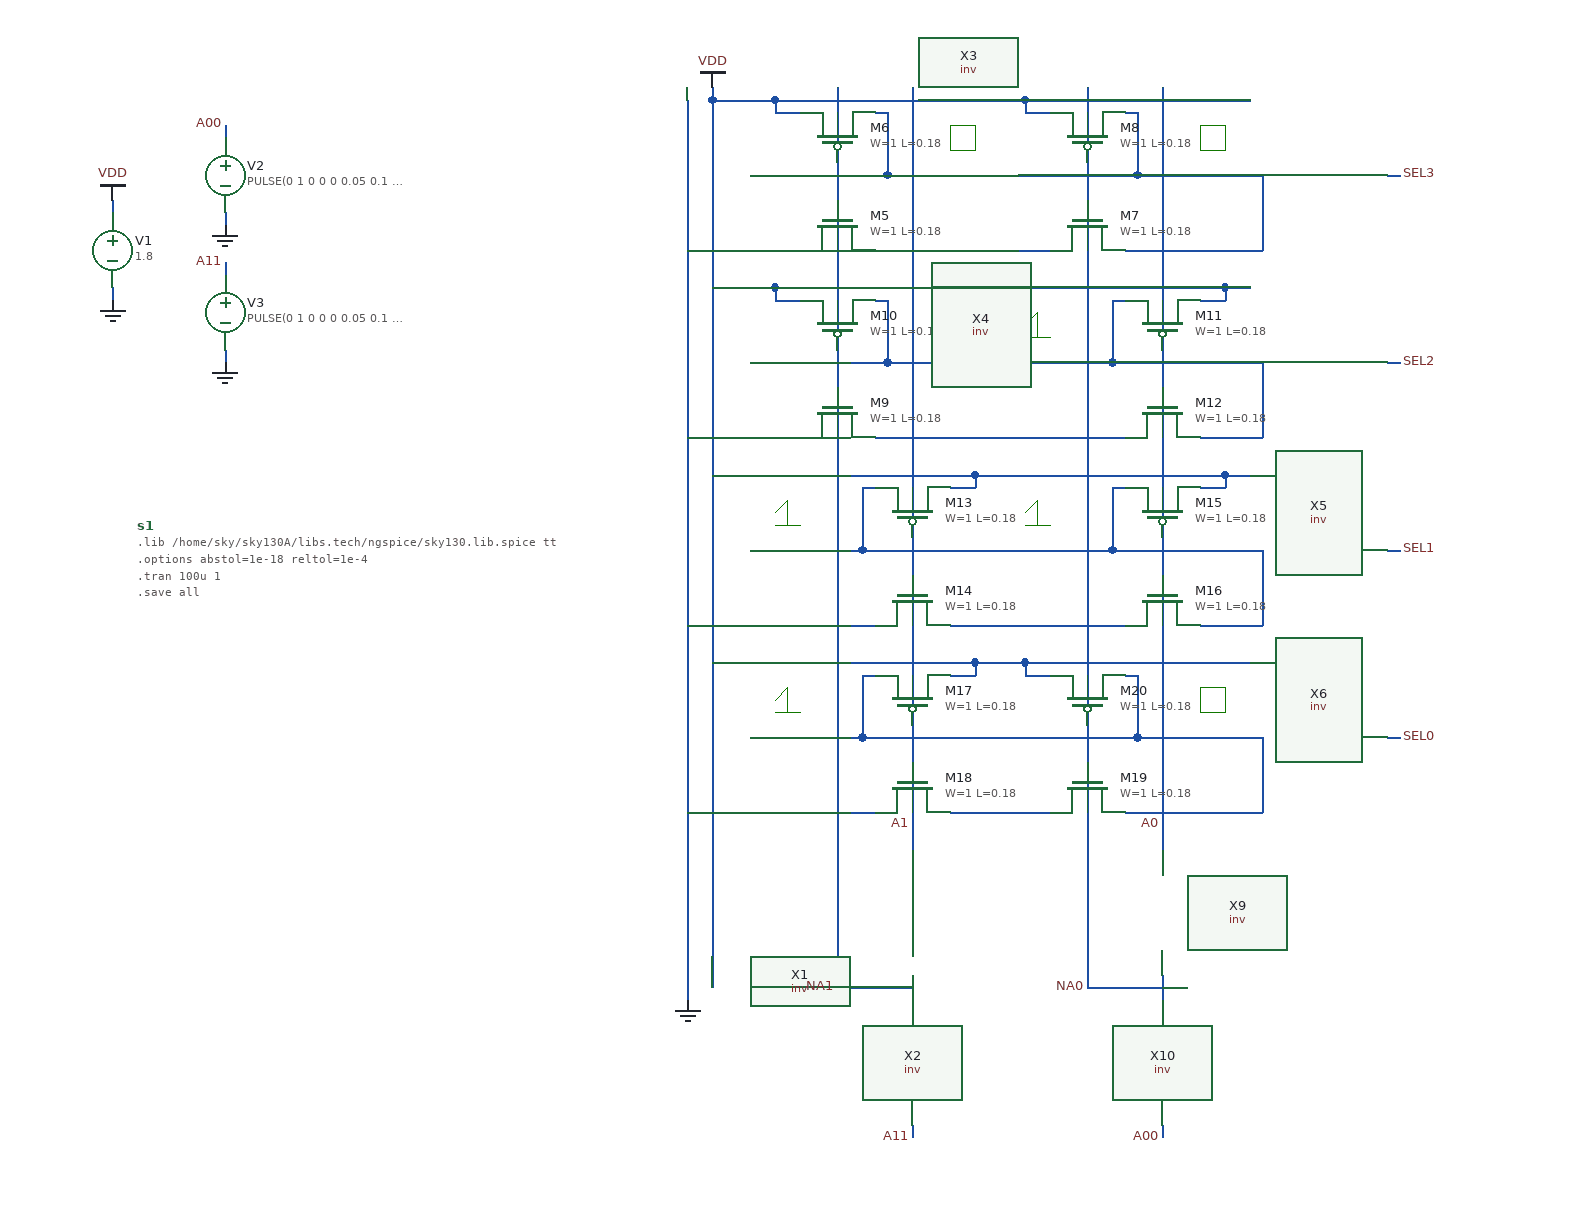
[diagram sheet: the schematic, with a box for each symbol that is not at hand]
v {xschem version=2.9.9 file_version=1.2 }
G {}
K {}
V {}
S {}
E {}
L 4 1500 -1330 1500 -1310 {}
L 4 1500 -1310 1520 -1310 {}
L 4 1520 -1330 1520 -1310 {}
L 4 1500 -1330 1520 -1330 {}
L 4 1700 -1330 1700 -1310 {}
L 4 1700 -1310 1720 -1310 {}
L 4 1720 -1330 1720 -1310 {}
L 4 1700 -1330 1720 -1330 {}
L 4 1500 -1180 1500 -1160 {}
L 4 1500 -1160 1520 -1160 {}
L 4 1520 -1180 1520 -1160 {}
L 4 1500 -1180 1520 -1180 {}
L 4 1560 -1170 1570 -1180 {}
L 4 1570 -1180 1570 -1160 {}
L 4 1560 -1160 1570 -1160 {}
L 4 1560 -1160 1580 -1160 {}
L 4 1360 -1020 1370 -1030 {}
L 4 1370 -1030 1370 -1010 {}
L 4 1360 -1010 1370 -1010 {}
L 4 1360 -1010 1380 -1010 {}
L 4 1560 -1020 1570 -1030 {}
L 4 1570 -1030 1570 -1010 {}
L 4 1560 -1010 1570 -1010 {}
L 4 1560 -1010 1580 -1010 {}
L 4 1360 -870 1370 -880 {}
L 4 1370 -880 1370 -860 {}
L 4 1360 -860 1370 -860 {}
L 4 1360 -860 1380 -860 {}
L 4 1700 -880 1700 -860 {}
L 4 1700 -860 1720 -860 {}
L 4 1720 -880 1720 -860 {}
L 4 1700 -880 1720 -880 {}
N 1360 -1340 1380 -1340 { lab=VDD}
N 1360 -1350 1360 -1340 { lab=VDD}
N 1340 -1350 1360 -1350 { lab=VDD}
N 1410 -1300 1410 -1270 { lab=NA1}
N 1410 -1270 1410 -1210 { lab=NA1}
N 1410 -1360 1410 -1300 { lab=NA1}
N 1440 -1340 1450 -1340 { lab=#net1}
N 1450 -1340 1450 -1290 { lab=#net1}
N 1340 -1290 1450 -1290 { lab=#net1}
N 1340 -1230 1380 -1230 { lab=GND}
N 1470 -1360 1470 -1210 { lab=A1}
N 1360 -1350 1540 -1350 { lab=VDD}
N 1450 -1290 1540 -1290 { lab=#net1}
N 1440 -1230 1540 -1230 { lab=#net2}
N 1560 -1340 1580 -1340 { lab=VDD}
N 1560 -1350 1560 -1340 { lab=VDD}
N 1540 -1350 1560 -1350 { lab=VDD}
N 1610 -1300 1610 -1270 { lab=NA0}
N 1610 -1270 1610 -1210 { lab=NA0}
N 1610 -1360 1610 -1300 { lab=NA0}
N 1640 -1340 1650 -1340 { lab=#net1}
N 1650 -1340 1650 -1290 { lab=#net1}
N 1540 -1290 1650 -1290 { lab=#net1}
N 1540 -1230 1580 -1230 { lab=#net2}
N 1670 -1360 1670 -1210 { lab=A0}
N 1560 -1350 1740 -1350 { lab=VDD}
N 1650 -1290 1740 -1290 { lab=#net1}
N 1640 -1230 1740 -1230 { lab=#net1}
N 1360 -1190 1380 -1190 { lab=VDD}
N 1360 -1200 1360 -1190 { lab=VDD}
N 1340 -1200 1360 -1200 { lab=VDD}
N 1410 -1150 1410 -1120 { lab=NA1}
N 1410 -1120 1410 -1060 { lab=NA1}
N 1410 -1210 1410 -1150 { lab=NA1}
N 1440 -1190 1450 -1190 { lab=#net3}
N 1450 -1190 1450 -1140 { lab=#net3}
N 1340 -1140 1450 -1140 { lab=#net3}
N 1340 -1080 1380 -1080 { lab=GND}
N 1470 -1210 1470 -1060 { lab=A1}
N 1360 -1200 1540 -1200 { lab=VDD}
N 1450 -1140 1540 -1140 { lab=#net3}
N 1440 -1080 1540 -1080 { lab=#net4}
N 1700 -1190 1720 -1190 { lab=VDD}
N 1720 -1200 1720 -1190 { lab=VDD}
N 1720 -1200 1740 -1200 { lab=VDD}
N 1540 -1200 1720 -1200 { lab=VDD}
N 1630 -1190 1640 -1190 { lab=#net3}
N 1630 -1190 1630 -1140 { lab=#net3}
N 1540 -1140 1630 -1140 { lab=#net3}
N 1630 -1140 1740 -1140 { lab=#net3}
N 1670 -1150 1670 -1120 { lab=A0}
N 1670 -1210 1670 -1150 { lab=A0}
N 1670 -1120 1670 -1060 { lab=A0}
N 1540 -1080 1640 -1080 { lab=#net4}
N 1700 -1080 1740 -1080 { lab=#net3}
N 1610 -1210 1610 -1060 { lab=NA0}
N 1500 -1040 1520 -1040 { lab=VDD}
N 1520 -1050 1520 -1040 { lab=VDD}
N 1520 -1050 1540 -1050 { lab=VDD}
N 1340 -1050 1520 -1050 { lab=VDD}
N 1430 -1040 1440 -1040 { lab=#net5}
N 1430 -1040 1430 -990 { lab=#net5}
N 1340 -990 1430 -990 { lab=#net5}
N 1430 -990 1540 -990 { lab=#net5}
N 1470 -1000 1470 -970 { lab=A1}
N 1470 -1060 1470 -1000 { lab=A1}
N 1470 -970 1470 -910 { lab=A1}
N 1340 -930 1440 -930 { lab=GND}
N 1500 -930 1540 -930 { lab=#net6}
N 1410 -1060 1410 -910 { lab=NA1}
N 1700 -1040 1720 -1040 { lab=VDD}
N 1720 -1050 1720 -1040 { lab=VDD}
N 1720 -1050 1740 -1050 { lab=VDD}
N 1540 -1050 1720 -1050 { lab=VDD}
N 1630 -1040 1640 -1040 { lab=#net5}
N 1630 -1040 1630 -990 { lab=#net5}
N 1540 -990 1630 -990 { lab=#net5}
N 1630 -990 1740 -990 { lab=#net5}
N 1670 -1000 1670 -970 { lab=A0}
N 1670 -1060 1670 -1000 { lab=A0}
N 1670 -970 1670 -910 { lab=A0}
N 1540 -930 1640 -930 { lab=#net6}
N 1700 -930 1740 -930 { lab=#net5}
N 1610 -1060 1610 -910 { lab=NA0}
N 1500 -890 1520 -890 { lab=VDD}
N 1520 -900 1520 -890 { lab=VDD}
N 1520 -900 1540 -900 { lab=VDD}
N 1340 -900 1520 -900 { lab=VDD}
N 1430 -890 1440 -890 { lab=#net7}
N 1430 -890 1430 -840 { lab=#net7}
N 1340 -840 1430 -840 { lab=#net7}
N 1430 -840 1540 -840 { lab=#net7}
N 1470 -850 1470 -820 { lab=A1}
N 1470 -910 1470 -850 { lab=A1}
N 1470 -820 1470 -760 { lab=A1}
N 1340 -780 1440 -780 { lab=GND}
N 1500 -780 1540 -780 { lab=#net8}
N 1410 -910 1410 -760 { lab=NA1}
N 1560 -890 1580 -890 { lab=VDD}
N 1560 -900 1560 -890 { lab=VDD}
N 1540 -900 1560 -900 { lab=VDD}
N 1610 -850 1610 -820 { lab=NA0}
N 1610 -820 1610 -760 { lab=NA0}
N 1610 -910 1610 -850 { lab=NA0}
N 1640 -890 1650 -890 { lab=#net7}
N 1650 -890 1650 -840 { lab=#net7}
N 1540 -840 1650 -840 { lab=#net7}
N 1540 -780 1580 -780 { lab=#net8}
N 1670 -910 1670 -760 { lab=A0}
N 1560 -900 1740 -900 { lab=VDD}
N 1650 -840 1740 -840 { lab=#net7}
N 1640 -780 1740 -780 { lab=#net7}
N 830 -1270 830 -1260 { lab=VDD}
N 830 -1200 830 -1190 { lab=GND}
N 920 -1260 920 -1250 { lab=GND}
N 920 -1150 920 -1140 { lab=GND}
N 920 -1220 920 -1210 { lab=A11}
N 920 -1330 920 -1320 { lab=A00}
N 1670 -650 1670 -630 { lab=NA0}
N 1670 -760 1670 -750 { lab=A0}
N 1640 -640 1670 -640 { lab=NA0}
N 1670 -530 1670 -520 { lab=A00}
N 1610 -760 1610 -640 { lab=NA0}
N 1610 -640 1640 -640 { lab=NA0}
N 1470 -650 1470 -630 { lab=NA1}
N 1470 -760 1470 -750 { lab=A1}
N 1440 -640 1470 -640 { lab=NA1}
N 1470 -530 1470 -520 { lab=A11}
N 1410 -760 1410 -640 { lab=NA1}
N 1410 -640 1440 -640 { lab=NA1}
N 1290 -1350 1290 -640 { lab=GND}
N 1310 -1350 1310 -640 { lab=VDD}
N 1310 -1360 1310 -1350 { lab=VDD}
N 1290 -640 1290 -630 { lab=GND}
N 1310 -1350 1340 -1350 { lab=VDD}
N 1290 -1230 1340 -1230 { lab=GND}
N 1310 -1200 1340 -1200 { lab=VDD}
N 1290 -1080 1340 -1080 { lab=GND}
N 1310 -1050 1340 -1050 { lab=VDD}
N 1290 -930 1340 -930 { lab=GND}
N 1310 -900 1340 -900 { lab=VDD}
N 1290 -780 1340 -780 { lab=GND}
N 1740 -1290 1750 -1290 { lab=#net1}
N 1750 -1290 1750 -1230 { lab=#net1}
N 1740 -1230 1750 -1230 { lab=#net1}
N 1740 -1140 1750 -1140 { lab=#net3}
N 1750 -1140 1750 -1080 { lab=#net3}
N 1740 -1080 1750 -1080 { lab=#net3}
N 1740 -990 1750 -990 { lab=#net5}
N 1750 -990 1750 -930 { lab=#net5}
N 1740 -930 1750 -930 { lab=#net5}
N 1740 -840 1750 -840 { lab=#net7}
N 1750 -840 1750 -780 { lab=#net7}
N 1740 -780 1750 -780 { lab=#net7}
N 1850 -840 1860 -840 { lab=SEL0}
N 1850 -990 1860 -990 { lab=SEL1}
N 1850 -1140 1860 -1140 { lab=SEL2}
N 1850 -1290 1860 -1290 { lab=SEL3}
C {sky130_fd_pr/nfet3_01v8.sym} 1410 -1250 1 0 {name=M5
L=0.18
W=1
body=GND
nf=1
mult=1
ad="'int((nf+1)/2) * W/nf * 0.29'" 
pd="'2*int((nf+1)/2) * (W/nf + 0.29)'"
as="'int((nf+2)/2) * W/nf * 0.29'" 
ps="'2*int((nf+2)/2) * (W/nf + 0.29)'"
nrd="'0.29 / W'" nrs="'0.29 / W'"
sa=0 sb=0 sd=0
model=nfet_01v8
spiceprefix=X
}
C {sky130_fd_pr/pfet3_01v8.sym} 1410 -1320 3 0 {name=M6
L=0.18
W=1
body=VDD
nf=1
mult=1
ad="'int((nf+1)/2) * W/nf * 0.29'" 
pd="'2*int((nf+1)/2) * (W/nf + 0.29)'"
as="'int((nf+2)/2) * W/nf * 0.29'" 
ps="'2*int((nf+2)/2) * (W/nf + 0.29)'"
nrd="'0.29 / W'" nrs="'0.29 / W'"
sa=0 sb=0 sd=0
model=pfet_01v8
spiceprefix=X
}
C {sky130_fd_pr/nfet3_01v8.sym} 1610 -1250 1 0 {name=M7
L=0.18
W=1
body=GND
nf=1
mult=1
ad="'int((nf+1)/2) * W/nf * 0.29'" 
pd="'2*int((nf+1)/2) * (W/nf + 0.29)'"
as="'int((nf+2)/2) * W/nf * 0.29'" 
ps="'2*int((nf+2)/2) * (W/nf + 0.29)'"
nrd="'0.29 / W'" nrs="'0.29 / W'"
sa=0 sb=0 sd=0
model=nfet_01v8
spiceprefix=X
}
C {sky130_fd_pr/pfet3_01v8.sym} 1610 -1320 3 0 {name=M8
L=0.18
W=1
body=VDD
nf=1
mult=1
ad="'int((nf+1)/2) * W/nf * 0.29'" 
pd="'2*int((nf+1)/2) * (W/nf + 0.29)'"
as="'int((nf+2)/2) * W/nf * 0.29'" 
ps="'2*int((nf+2)/2) * (W/nf + 0.29)'"
nrd="'0.29 / W'" nrs="'0.29 / W'"
sa=0 sb=0 sd=0
model=pfet_01v8
spiceprefix=X
}
C {sky130_fd_pr/nfet3_01v8.sym} 1410 -1100 1 0 {name=M9
L=0.18
W=1
body=GND
nf=1
mult=1
ad="'int((nf+1)/2) * W/nf * 0.29'" 
pd="'2*int((nf+1)/2) * (W/nf + 0.29)'"
as="'int((nf+2)/2) * W/nf * 0.29'" 
ps="'2*int((nf+2)/2) * (W/nf + 0.29)'"
nrd="'0.29 / W'" nrs="'0.29 / W'"
sa=0 sb=0 sd=0
model=nfet_01v8
spiceprefix=X
}
C {sky130_fd_pr/pfet3_01v8.sym} 1410 -1170 3 0 {name=M10
L=0.18
W=1
body=VDD
nf=1
mult=1
ad="'int((nf+1)/2) * W/nf * 0.29'" 
pd="'2*int((nf+1)/2) * (W/nf + 0.29)'"
as="'int((nf+2)/2) * W/nf * 0.29'" 
ps="'2*int((nf+2)/2) * (W/nf + 0.29)'"
nrd="'0.29 / W'" nrs="'0.29 / W'"
sa=0 sb=0 sd=0
model=pfet_01v8
spiceprefix=X
}
C {sky130_fd_pr/pfet3_01v8.sym} 1670 -1170 1 1 {name=M11
L=0.18
W=1
body=VDD
nf=1
mult=1
ad="'int((nf+1)/2) * W/nf * 0.29'" 
pd="'2*int((nf+1)/2) * (W/nf + 0.29)'"
as="'int((nf+2)/2) * W/nf * 0.29'" 
ps="'2*int((nf+2)/2) * (W/nf + 0.29)'"
nrd="'0.29 / W'" nrs="'0.29 / W'"
sa=0 sb=0 sd=0
model=pfet_01v8
spiceprefix=X
}
C {sky130_fd_pr/nfet3_01v8.sym} 1670 -1100 3 1 {name=M12
L=0.18
W=1
body=GND
nf=1
mult=1
ad="'int((nf+1)/2) * W/nf * 0.29'" 
pd="'2*int((nf+1)/2) * (W/nf + 0.29)'"
as="'int((nf+2)/2) * W/nf * 0.29'" 
ps="'2*int((nf+2)/2) * (W/nf + 0.29)'"
nrd="'0.29 / W'" nrs="'0.29 / W'"
sa=0 sb=0 sd=0
model=nfet_01v8
spiceprefix=X
}
C {sky130_fd_pr/pfet3_01v8.sym} 1470 -1020 1 1 {name=M13
L=0.18
W=1
body=VDD
nf=1
mult=1
ad="'int((nf+1)/2) * W/nf * 0.29'" 
pd="'2*int((nf+1)/2) * (W/nf + 0.29)'"
as="'int((nf+2)/2) * W/nf * 0.29'" 
ps="'2*int((nf+2)/2) * (W/nf + 0.29)'"
nrd="'0.29 / W'" nrs="'0.29 / W'"
sa=0 sb=0 sd=0
model=pfet_01v8
spiceprefix=X
}
C {sky130_fd_pr/nfet3_01v8.sym} 1470 -950 3 1 {name=M14
L=0.18
W=1
body=GND
nf=1
mult=1
ad="'int((nf+1)/2) * W/nf * 0.29'" 
pd="'2*int((nf+1)/2) * (W/nf + 0.29)'"
as="'int((nf+2)/2) * W/nf * 0.29'" 
ps="'2*int((nf+2)/2) * (W/nf + 0.29)'"
nrd="'0.29 / W'" nrs="'0.29 / W'"
sa=0 sb=0 sd=0
model=nfet_01v8
spiceprefix=X
}
C {sky130_fd_pr/pfet3_01v8.sym} 1670 -1020 1 1 {name=M15
L=0.18
W=1
body=VDD
nf=1
mult=1
ad="'int((nf+1)/2) * W/nf * 0.29'" 
pd="'2*int((nf+1)/2) * (W/nf + 0.29)'"
as="'int((nf+2)/2) * W/nf * 0.29'" 
ps="'2*int((nf+2)/2) * (W/nf + 0.29)'"
nrd="'0.29 / W'" nrs="'0.29 / W'"
sa=0 sb=0 sd=0
model=pfet_01v8
spiceprefix=X
}
C {sky130_fd_pr/nfet3_01v8.sym} 1670 -950 3 1 {name=M16
L=0.18
W=1
body=GND
nf=1
mult=1
ad="'int((nf+1)/2) * W/nf * 0.29'" 
pd="'2*int((nf+1)/2) * (W/nf + 0.29)'"
as="'int((nf+2)/2) * W/nf * 0.29'" 
ps="'2*int((nf+2)/2) * (W/nf + 0.29)'"
nrd="'0.29 / W'" nrs="'0.29 / W'"
sa=0 sb=0 sd=0
model=nfet_01v8
spiceprefix=X
}
C {sky130_fd_pr/pfet3_01v8.sym} 1470 -870 1 1 {name=M17
L=0.18
W=1
body=VDD
nf=1
mult=1
ad="'int((nf+1)/2) * W/nf * 0.29'" 
pd="'2*int((nf+1)/2) * (W/nf + 0.29)'"
as="'int((nf+2)/2) * W/nf * 0.29'" 
ps="'2*int((nf+2)/2) * (W/nf + 0.29)'"
nrd="'0.29 / W'" nrs="'0.29 / W'"
sa=0 sb=0 sd=0
model=pfet_01v8
spiceprefix=X
}
C {sky130_fd_pr/nfet3_01v8.sym} 1470 -800 3 1 {name=M18
L=0.18
W=1
body=GND
nf=1
mult=1
ad="'int((nf+1)/2) * W/nf * 0.29'" 
pd="'2*int((nf+1)/2) * (W/nf + 0.29)'"
as="'int((nf+2)/2) * W/nf * 0.29'" 
ps="'2*int((nf+2)/2) * (W/nf + 0.29)'"
nrd="'0.29 / W'" nrs="'0.29 / W'"
sa=0 sb=0 sd=0
model=nfet_01v8
spiceprefix=X
}
C {sky130_fd_pr/nfet3_01v8.sym} 1610 -800 1 0 {name=M19
L=0.18
W=1
body=GND
nf=1
mult=1
ad="'int((nf+1)/2) * W/nf * 0.29'" 
pd="'2*int((nf+1)/2) * (W/nf + 0.29)'"
as="'int((nf+2)/2) * W/nf * 0.29'" 
ps="'2*int((nf+2)/2) * (W/nf + 0.29)'"
nrd="'0.29 / W'" nrs="'0.29 / W'"
sa=0 sb=0 sd=0
model=nfet_01v8
spiceprefix=X
}
C {sky130_fd_pr/pfet3_01v8.sym} 1610 -870 3 0 {name=M20
L=0.18
W=1
body=VDD
nf=1
mult=1
ad="'int((nf+1)/2) * W/nf * 0.29'" 
pd="'2*int((nf+1)/2) * (W/nf + 0.29)'"
as="'int((nf+2)/2) * W/nf * 0.29'" 
ps="'2*int((nf+2)/2) * (W/nf + 0.29)'"
nrd="'0.29 / W'" nrs="'0.29 / W'"
sa=0 sb=0 sd=0
model=pfet_01v8
spiceprefix=X
}
C {devices/vsource.sym} 830 -1230 0 0 {name=V1 value=1.8}
C {devices/vsource.sym} 920 -1290 0 0 {name=V2 value="PULSE(0 1 0 0 0 0.05 0.1 0)"}
C {devices/vsource.sym} 920 -1180 0 0 {name=V3 value="PULSE(0 1 0 0 0 0.05 0.1 0)"}
C {devices/vdd.sym} 830 -1270 0 0 {name=l1 lab=VDD}
C {devices/gnd.sym} 830 -1190 0 0 {name=l2 lab=GND}
C {devices/gnd.sym} 920 -1250 0 0 {name=l3 lab=GND}
C {devices/gnd.sym} 920 -1140 0 0 {name=l4 lab=GND}
C {devices/lab_pin.sym} 920 -1330 0 0 {name=l7 sig_type=std_logic lab=A00}
C {devices/lab_pin.sym} 920 -1220 0 0 {name=l8 sig_type=std_logic lab=A11}
C {/home/sky/Desktop/cochlea_sky130/xschem/HW4_RAM_readout/inv/inv.sym} 1670 -700 3 0 {name=X9}
C {/home/sky/Desktop/cochlea_sky130/xschem/HW4_RAM_readout/inv/inv.sym} 1670 -580 3 0 {name=X10}
C {devices/lab_pin.sym} 1670 -520 0 0 {name=l9 sig_type=std_logic lab=A00}
C {devices/lab_pin.sym} 1610 -640 0 0 {name=l12 sig_type=std_logic lab=NA0}
C {/home/sky/Desktop/cochlea_sky130/xschem/HW4_RAM_readout/inv/inv.sym} 1470 -700 3 0 {name=X1}
C {/home/sky/Desktop/cochlea_sky130/xschem/HW4_RAM_readout/inv/inv.sym} 1470 -580 3 0 {name=X2}
C {devices/lab_pin.sym} 1470 -520 0 0 {name=l5 sig_type=std_logic lab=A11}
C {devices/lab_pin.sym} 1410 -640 0 0 {name=l6 sig_type=std_logic lab=NA1}
C {devices/lab_pin.sym} 1670 -770 0 0 {name=l10 sig_type=std_logic lab=A0}
C {devices/lab_pin.sym} 1470 -770 0 0 {name=l11 sig_type=std_logic lab=A1}
C {devices/vdd.sym} 1310 -1360 0 0 {name=l13 lab=VDD}
C {devices/gnd.sym} 1290 -630 0 0 {name=l14 lab=GND}
C {/home/sky/Desktop/cochlea_sky130/xschem/HW4_RAM_readout/inv/inv.sym} 1800 -1290 0 0 {name=X3}
C {/home/sky/Desktop/cochlea_sky130/xschem/HW4_RAM_readout/inv/inv.sym} 1800 -1140 0 0 {name=X4}
C {/home/sky/Desktop/cochlea_sky130/xschem/HW4_RAM_readout/inv/inv.sym} 1800 -990 0 0 {name=X5}
C {/home/sky/Desktop/cochlea_sky130/xschem/HW4_RAM_readout/inv/inv.sym} 1800 -840 0 0 {name=X6}
C {devices/code.sym} 850 -1010 0 0 {name=s1 only_toplevel=false value="
.lib /home/sky/sky130A/libs.tech/ngspice/sky130.lib.spice tt
.options abstol=1e-18 reltol=1e-4
.tran 100u 1
.save all
"}
C {devices/lab_pin.sym} 1860 -840 2 0 {name=l15 sig_type=std_logic lab=SEL0}
C {devices/lab_pin.sym} 1860 -990 2 0 {name=l16 sig_type=std_logic lab=SEL1}
C {devices/lab_pin.sym} 1860 -1140 2 0 {name=l17 sig_type=std_logic lab=SEL2}
C {devices/lab_pin.sym} 1860 -1290 2 0 {name=l18 sig_type=std_logic lab=SEL3}
